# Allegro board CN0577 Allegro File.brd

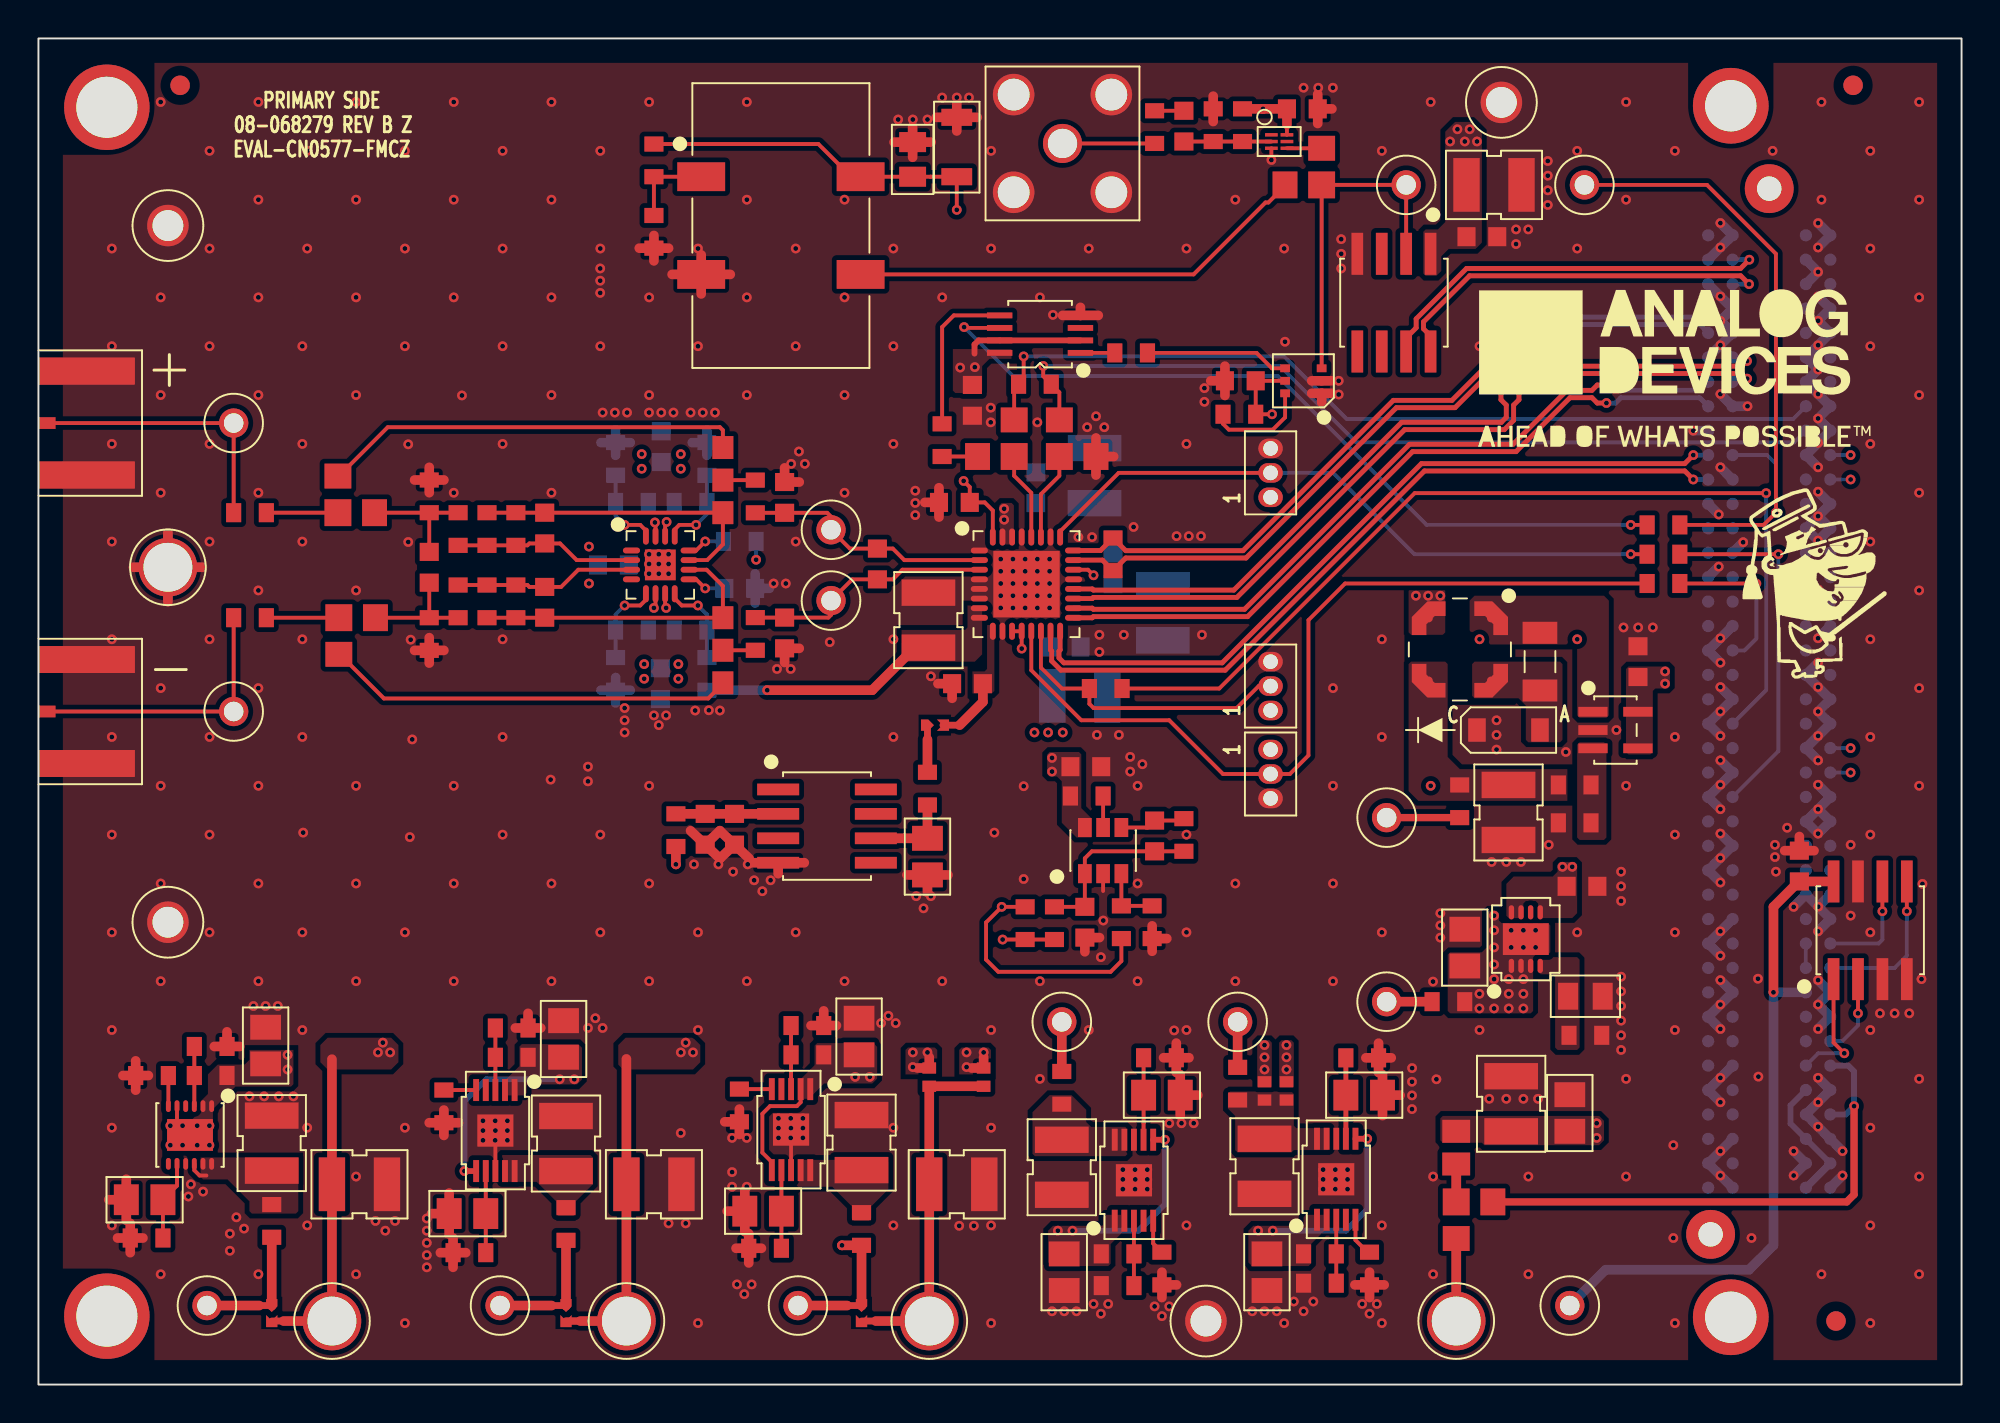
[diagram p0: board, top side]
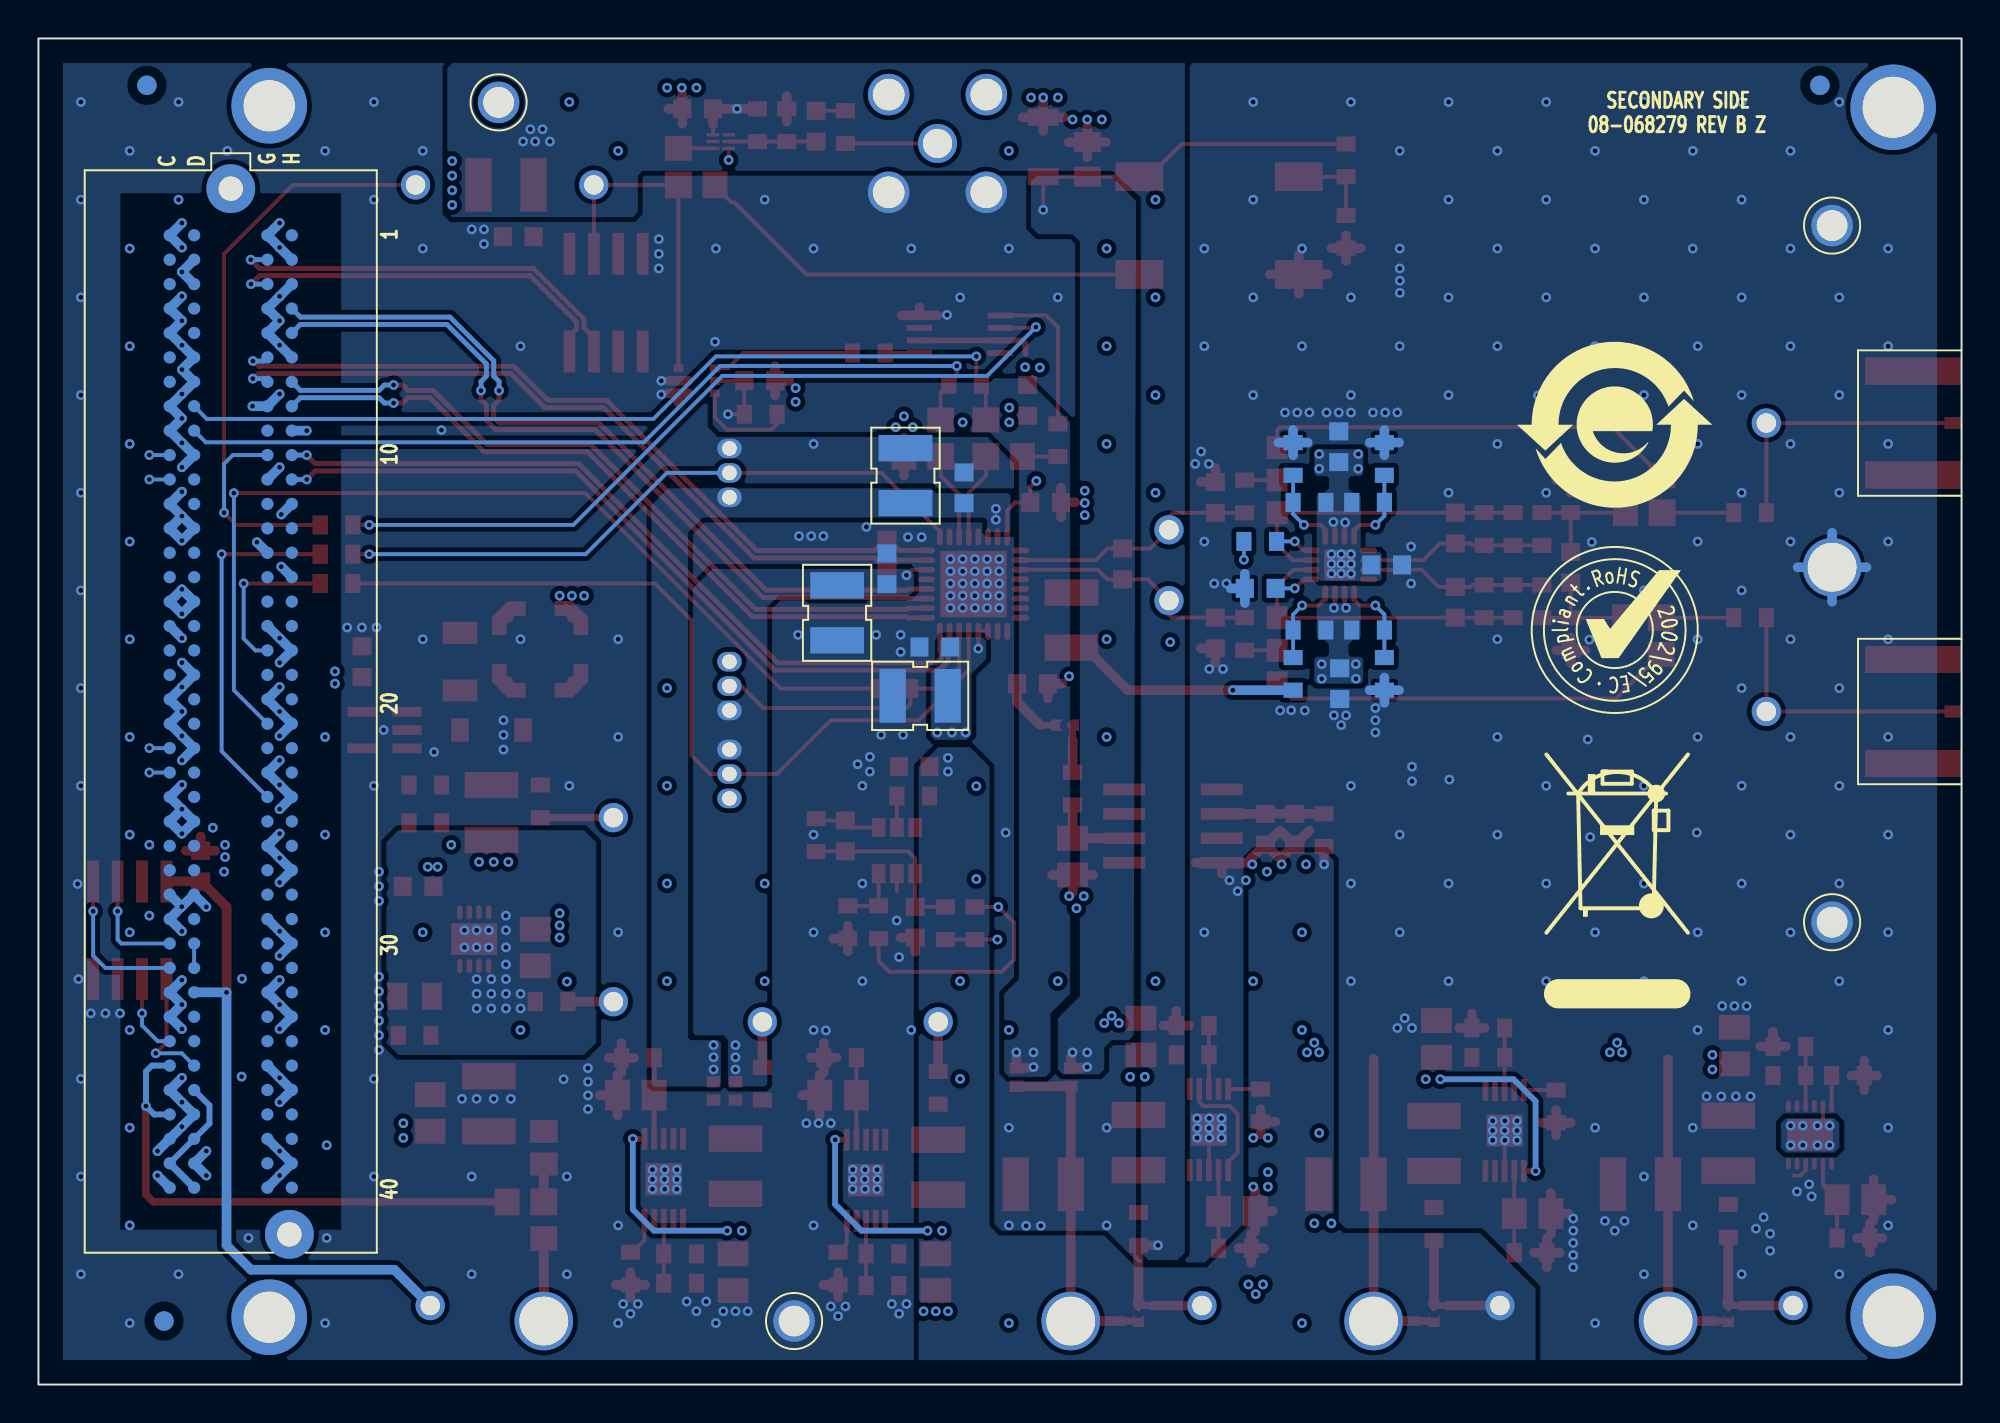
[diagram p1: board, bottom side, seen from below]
Outline 100 x 70 mm; copper layers: TOP, L2_GND, L3_PWR, BOTTOM. Coordinates in mm from the lower left corner of the outline.
Outline path: rectangle 0,0 100,70

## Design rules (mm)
constraint set DEFAULT: 
net group CLK: nets CLK+ CLK-
net group DA: nets DA+ DA-
net group DB: nets DB+ DB-
net group DCO: nets DCO+ DCO-
net group LVDS_CLK: nets LVDS_CLK+ LVDS_CLK-

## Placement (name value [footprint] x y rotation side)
A1  ADA4807-1ARJZ  [SOT23_6-2]  55.36 27.77 0 top
C1  1uF  [C0603]  34.67 28.88 90 top
C2  0.1uF  [C0603]  36.2 28.88 270 top
C3  10UF  [C1210H110]  47.75 10.41 0 top
C4  4.7uF  [C0805H53]  42.67 18.1 90 top
C5  4.7uF  [C0805H53]  46.23 27.45 270 top
C6  0.1uF  [C0603]  54.46 32.13 0 top
C7  TBD0603  [C0603]  58.04 28.53 270 top
C8  TBD0603  [C0603]  54.41 24.04 270 top
C9  10UF  [C1210H110]  16.69 10.41 0 top
C10  1uF  [C0603]  83.17 37.59 270 top
C11  4.7uF  [C0805H53]  79.63 14.12 270 top
C12  1uF  [C0603]  80.26 25.91 180 top
C13  1UF  [C1206]  78.08 37.59 270 top
C14  10UF  [C1210H110]  76.58 14.6 90 top
C15  10PF  [C0805H30]  80.44 20.19 180 top
C16  4.7uF  [C0805H53]  74.17 22.72 270 top
C17  10UF  [C1210H110]  76.44 29.75 270 top
C18  10UF  [C1210H110]  32 10.41 0 top
C19  4.7uF  [C0805H53]  27.3 17.97 90 top
C20  4.7uF  [C0805H53]  53.34 5.84 270 top
C21  4.7uF  [C0805H53]  63.88 5.84 270 top
C22  4.7uF  [C0805H53]  11.81 17.63 90 top
C23  4.7uF  [C0805H53]  22.31 8.89 180 top
C24  4.7uF  [C0805H53]  58.42 15.05 0 top
C25  4.7uF  [C0805H53]  68.94 15.05 0 top
C26  4.7uF  [C0805H53]  5.52 9.61 180 top
C27  10UF  [C1210H110]  27.43 12.53 90 top
C28  10UF  [C1210H110]  53.21 11.3 270 top
C29  10UF  [C1210H110]  63.75 11.35 270 top
C30  10UF  [C1210H110]  12.13 12.56 90 top
C31  0.1uF  [C0603]  75.06 59.69 0 top
C32  10UF  [C1210H110]  75.69 62.38 0 top
C33  0.1uF  [C0603]  29.89 42.62 180 bottom
C34  0.1uF  [C0603]  62.5 52.2 180 top
C41  TBD0603  [C0603]  43.63 42.67 270 top
C42  82pF  [C0603]  38.8 46.13 90 top
C43  82pF  [C0603]  38.8 39.08 270 top
C44  0.1uF  [C0603]  48.31 36.45 180 top
C45  0.1uF  [C0603]  47.63 45.87 180 top
C46  10UF  [C1210H110]  46.28 39.75 90 top
C47  10UF  [C1210H110]  54.91 47.27 90 bottom
C48  10UF  [C1210H110]  54.15 35.81 0 bottom
C49  0.1uF  [C0603]  53.39 38.35 0 bottom
C50  0.1uF  [C0603]  51.87 46.63 90 bottom
C51  0.1uF  [C0603]  55.88 42.42 90 bottom
C52  10UF  [C1210H110]  58.47 40.13 270 bottom
C53  0.1uF  [C0603]  91.57 26.96 90 top
C56  1.8pF  [C0603]  20.32 42.5 270 top
C57  0.1uF  [C0603]  32.38 48.77 90 bottom
C58  1.8pF  [C0603]  26.32 40.68 270 top
C59  0.1uF  [C0603]  32.34 36.45 270 bottom
C60  1.8pF  [C0603]  26.32 44.54 90 top
C61  0.1uF  [C0603]  36.47 41.4 0 bottom
C62  10PF  [C0805H30]  45.46 63.71 270 top
C63  22uF  [C1206H71-2]  47.75 64.35 90 top
C64  0.1uF  [C0603]  59.56 65.44 270 top
C65  0.1uF  [C0603]  65.72 66.34 0 top
C66  0.1uF  [C0603]  48.56 51.18 270 top
C67  4.7uF  [C0805H53]  37.68 9.02 180 top
C68  10UF  [C1210H110]  42.8 12.58 90 top
D1  MBR0520LT1G  [SOD123-2]  76.44 34.04 0 top
E1  600OHM AT 100MEGHZ  [L0805]  73.72 12.32 90 top
E2  30OHM AT 100MEGHZ  [L0402]  64.9 15.27 90 top
E3  30OHM AT 100MEGHZ  [L0402]  63.75 15.27 90 top
E4  30OHM AT 100MEGHZ  [L0402]  46.32 15.98 90 top
E5  30OHM AT 100MEGHZ  [L0402]  49.15 15.98 90 top
EXTPWR  2501-2-00-80-00-00-07-0  [CNMILLMAX2501]  73.72 3.3 0 top
GND  2501-2-00-80-00-00-07-0  [CNMILLMAX2501]  6.73 42.5 0 top
J1  60312202114513  [CNSMARAL559W250H131]  0 50 180 top
J2  60312202114513  [CNSMARAL559W250H131]  0 35 180 top
J3  5-1814832-2  [CNTYCO1814832]  53.25 64.54 0 top
JP2  3PIN_JUMPER_SM  [3PINJUMPER_0603]  74.68 9.5 180 top
JP6  3PINJUMPER0603  [JUMPER0603_3P]  35.59 47.03 90 top
JP7  3PINJUMPER0603  [JUMPER0603_3P]  35.59 38.18 270 top
JP9  3PIN_JUMPER_SM  [3PINJUMPER_0603]  49.78 48.26 0 top
JP10  3PIN_JUMPER_SM  [3PINJUMPER_0603]  53.09 49.21 270 top
JP11  3PIN_JUMPER_SM  [3PINJUMPER_0603]  15.57 46.29 270 top
JP12  3PIN_JUMPER_SM  [3PINJUMPER_0603]  16.57 39.88 180 top
JP14  3PIN_JUMPER_SM  [3PINJUMPER_0603]  65.77 62.38 0 top
L1  10uH  [LSMSQ189H118]  73.91 38.23 180 top
NOREF  -  []  362.42 198.88 0 top
NOREF#2  -  []  0 70 0 top
NOREF#3  -  []  0 0 0 top
NOREF#4  -  [unnamed#2]  88 66.5 0 top
NOREF#5  -  []  100 0 0 top
NOREF#6  -  []  7.62 323.21 0 top
NOREF#7  -  []  271.84 198.88 0 top
NOREF#8  -  [unnamed#2]  93.47 3.3 0 top
NOREF#9  -  []  100 0 90 top
NOREF#10  -  []  147 173.93 0 top
NOREF#11  -  [unnamed#2]  94.36 67.56 0 top
NOREF#12  -  []  74.3 229.24 0 top
NOREF#13  -  []  100 0 90 top
NOREF#14  -  []  362.75 209.04 0 top
NOREF#15  -  []  92.36 41.66 0 top
NOREF#16  -  []  -76.2 -76.2 0 top
NOREF#17  -  [unnamed#2]  88 3.5 0 top
NOREF#18  -  []  100 70 180 top
NOREF#19  -  []  284.29 209.04 90 top
NOREF#20  -  []  65.79 170.81 270 top
NOREF#21  -  []  3.56 3.56 0 top
NOREF#22  -  []  0 70 270 top
NOREF#23  -  []  84.5 52.83 0 top
NOREF#24  -  []  -76.2 -76.2 0 top
NOREF#25  -  []  0 0 0 top
NOREF#26  -  []  -7.24 105.28 0 top
NOREF#27  -  []  271.84 184.91 0 top
NOREF#28  -  [unnamed#2]  7.37 67.56 0 top
NOREF#29  -  []  350.02 90.8 0 top
NOREF#30  -  []  -56.01 289.94 0 top
NOREF#31  -  []  338.9 195.07 0 top
NOREF#32  -  []  -76.2 -76.2 0 top
NOREF#33  -  [unnamed#2]  3.56 66.42 0 top
NOREF#34  -  [unnamed#2]  3.56 3.56 0 top
NOREF#35  -  []  0 70 0 top
NOREF#36  -  []  0 0 0 top
NOREF#37  -  []  3.56 3.56 0 top
NOREF#38  -  []  394.78 203.96 0 top
NOREF#39  -  [unnamed#2]  93.47 3.3 180 bottom
NOREF#40  -  []  18.03 39.24 180 bottom
NOREF#41  -  []  18.03 49.91 180 bottom
NOREF#42  -  []  8.64 36.45 180 bottom
NOREF#43  -  [unnamed#2]  94.36 67.56 180 bottom
NOREF#44  -  [unnamed#2]  7.37 67.56 180 bottom
P1  FTS-103-01-F-S  [CN1X3H159]  64.07 33.02 270 top
P2  FTS-103-01-F-S  [CN1X3H159]  64.07 35.05 90 top
P3  FTS-103-01-F-S  [CN1X3H159]  64.07 46.14 90 top
P4  ASP-134604-01  [CNSAMTECASP-134604-01]  90 35 270 bottom
P5  NCSOLDER_BRIDGE  [NCSB]  46.61 34.29 0 top
P6  NCSOLDER_BRIDGE  [NCSB]  27.43 3.73 270 top
P7  NCSOLDER_BRIDGE  [NCSB]  12.13 3.73 270 top
P8  NCSOLDER_BRIDGE  [NCSB]  42.8 3.73 270 top
R1  0  [R0603]  33.15 28.83 90 top
R2  100K  [R0603]  39.98 17.14 0 top
R3  0  [R0603]  46.23 30.99 90 top
R4  0  [R0603]  56.31 24.04 90 top
R5  0  [R0603]  54.51 30.61 180 top
R6  TBD0603  [R0603]  57.91 24.04 270 top
R7  0  [R0603]  51.31 23.99 270 top
R8  0  [R0603]  59.56 28.58 270 top
R9  0  [R0603]  52.83 23.99 270 top
R10  750K  [R0603]  80.44 18.16 180 top
R11  18.2K  [R0603]  79.88 31.18 180 top
R12  13K  [R0603]  79.88 29.21 0 top
R13  0  [R0603]  73.32 19.91 180 top
R14  0  [R0603]  73.9 30.33 270 top
R15  100K  [R0603]  24.61 17.02 0 top
R16  22.1K  [R0603]  24.61 18.54 180 top
R17  100K  [R0603]  56.12 6.79 180 top
R18  22.1K  [R0603]  56.12 5.14 0 top
R19  100K  [R0603]  66.64 6.79 180 top
R20  22.1K  [R0603]  66.64 5.27 180 top
R21  100K  [R0603]  8.95 16.07 0 top
R22  80.6K  [R0603]  8.95 17.58 180 top
R23  68.1K  [R0603]  22.41 6.86 180 top
R24  51.1K  [R0603]  58.32 16.99 180 top
R25  24.9K  [R0603]  68.83 16.99 180 top
R26  4.99K  [R0603]  5.62 7.62 0 top
R27  1.5K  [R0603]  21.08 14.46 90 top
R28  1.5K  [R0603]  58.42 6.03 90 top
R29  39.2K  [R0603]  5.91 16.07 0 top
R30  1.21K  [R0603]  69.22 6.03 90 top
R31  0  [R0603]  27.43 8.35 270 top
R32  1K  [R0603]  84.5 41.66 0 top
R33  0  [R0603]  53.21 15.43 90 top
R34  1K  [R0603]  84.5 43.18 0 top
R35  0  [R0603]  62.36 15.65 90 top
R36  0  [R0603]  12.13 8.51 270 top
R37  0  [R0603]  62.45 50.46 0 top
R45  1K  [R0603]  32 63.66 90 top
R46  1K  [R0603]  32 59.94 90 top
R53  24.9  [R0603]  37.28 46.18 270 top
R54  24.9  [R0603]  37.28 39.03 90 top
R55  1K  [R0603]  55.5 36.2 0 top
R56  100  [R0603]  51.82 52.02 0 top
R57  100  [R0603]  55.88 43.17 270 top
R58  0  [R0603]  11 39.88 180 top
R59  0  [R0603]  11 45.34 180 top
R60  0  [R0603]  20.32 46.19 270 top
R61  0  [R0603]  20.32 39.03 270 top
R62  1K  [R0603]  21.82 44.49 270 top
R63  1K  [R0603]  21.82 40.73 90 top
R64  0  [R0603]  30.01 36.96 90 bottom
R65  0  [R0603]  30.01 48.13 270 bottom
R66  0  [R0603]  30.86 39.24 180 bottom
R67  0  [R0603]  30.86 45.87 180 bottom
R68  20K  [R0603]  24.82 40.73 270 top
R69  1K  [R0603]  23.32 40.73 270 top
R70  20K  [R0603]  24.82 44.49 90 top
R71  0  [R0603]  33.91 39.24 0 bottom
R72  1K  [R0603]  23.32 44.49 90 top
R73  0  [R0603]  33.91 45.87 0 bottom
R74  0  [R0603]  34.76 36.96 270 bottom
R75  0  [R0603]  34.76 48.13 90 bottom
R76  0  [R0603]  36.47 43.84 180 bottom
R77  49.9  [R0603]  58.04 65.39 90 top
R78  1K  [R0603]  62.61 65.49 90 top
R79  1K  [R0603]  61.09 65.49 270 top
R80  33.2  [R0603]  56.82 53.65 180 top
R82  33.2  [R0603]  84.5 44.7 180 top
R83  33.2  [R0603]  46.99 49.11 270 top
R84  22.1K  [R0603]  39.98 18.67 180 top
R85  33.2K  [R0603]  37.78 7.09 180 top
R86  1.21K  [R0603]  36.45 14.51 90 top
R88  0  [R0603]  42.8 8.09 270 top
TP1  RED  [CNKEY5001TP]  70.1 19.91 0 top
TP2  BLK  [CNKEY5005-9TP]  6.73 24.04 0 top
TP3  RED  [CNKEY5001TP]  70.1 29.48 0 top
TP4  BLK  [CNKEY5005-9TP]  6.73 60.27 0 top
TP5  BLK  [CNKEY5005-9TP]  76.07 66.67 0 top
TP6  BLK  [CNKEY5005-9TP]  60.71 3.3 0 top
TP7  RED  [CNKEY5001TP]  24 4.11 0 top
TP8  RED  [CNKEY5001TP]  53.21 18.86 0 top
TP9  RED  [CNKEY5001TP]  62.36 18.86 0 top
TP10  RED  [CNKEY5001TP]  8.76 4.11 0 top
TP11  RED  [CNKEY5001TP]  41.21 44.45 0 top
TP12  RED  [CNKEY5001TP]  41.21 40.77 0 top
TP13  RED  [CNKEY5001TP]  79.63 4.11 0 top
TP14  RED  [CNKEY5001TP]  10.15 50 0 top
TP15  RED  [CNKEY5001TP]  10.15 35 0 top
TP16  RED  [CNKEY5001TP]  71.12 62.38 0 top
TP17  RED  [CNKEY5001TP]  80.39 62.38 0 top
TP18  RED  [CNKEY5001TP]  39.5 4.11 0 top
U1  LTC2387CUH-18#PBF  [QFN32_5X5_PAD3_45X3_45]  51.38 41.62 270 top
U2  ADR4520ARZ  [SO8]  41 29.04 270 top
U3  LT1931ES5#TRMPBF  [TSOT-5]  82 34.04 270 top
U4  LT3080EDD#PBF  [DFN8_3X3_PAD2_38X1_65]  77.34 23.16 0 top
U5  LT3042EMSE#PBF  [MSOP10_PAD1_88X1_68]  23.76 13.21 180 top
U6  LT3042EMSE#PBF  [MSOP10_PAD1_88X1_68]  56.96 10.62 0 top
U7  LT3042EMSE#PBF  [MSOP10_PAD1_88X1_68]  67.48 10.67 0 top
U8  LT3094EDD#PBF  [DFN12_3X3_PAD2_38X1_65]  7.88 12.98 180 top
U9  M24C02-RMN6TP  [SO8]  95.25 23.62 0 top
U10  ADA4945-1ACPZ-R7  [QFN16_3X3_PAD1_6X1_6]  32.34 42.62 270 top
U11  ADG3241BKSZ  [SC70-6]  65.78 52.2 90 top
U12  74LVC1G04FW4-7  [DFN6_1X1]  64.52 64.64 270 top
U13  SN74LVC1G74DCTR  [MSOP8-2]  52.08 54.62 90 top
U14  LT3042EMSE#PBF  [MSOP10_PAD1_88X1_68]  39.13 13.26 180 top
U15  ADN4661BRZ  [SO8]  70.48 56.26 180 top
UNK3.3V  2501-2-00-80-00-00-07-0  [CNMILLMAX2501]  46.32 3.3 0 top
UNK+6.8V  2501-2-00-80-00-00-07-0  [CNMILLMAX2501]  30.57 3.3 90 top
UNK-1V  2501-2-00-80-00-00-07-0  [CNMILLMAX2501]  15.26 3.3 0 top
Y1  120MEGHZ  [YSML563W343H217_A]  38.61 60.27 270 top

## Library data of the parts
A1 = ADA4807_1: User Part Number: UPN; Tolerance: N/A; alternate symbols: (); part number: ADA4807_1_SM-ADA4807-1ARJZ,E024029,SOT23_6-2; tolerance: N/A
C1 C10 C12 = CAP: User Part Number: UPN; Tolerance: 10; alternate symbols: (C0603L); part number: CAP_SM-1UF,25V,10,E026591,C0603; tolerance: 10
C2 C6 C31 C33 C34 C44 C45 C49-C51 C53 C57 C59 C61 C64-C66 = CAP: User Part Number: UPN; Tolerance: 10; alternate symbols: (C0603L); part number: CAP_SM-0.1UF,16V,10,E026560,C0603; tolerance: 10
C3 C9 C14 C17 C18 C27-C30 C32 C46-C48 C52 C68 = CAP: Tolerance: 10; User Part Number: UPN; alternate symbols: (); part number: CAP_SM-10UF,50V,10,E048108,C1210H110; tolerance: 10
C4 C5 C11 C16 C19-C26 C67 = CAP: Tolerance: 10; User Part Number: UPN; alternate symbols: (); part number: CAP_SM-4.7UF,25V,10,E025752,C0805H53; tolerance: 10
C7 C8 C41 = CAP: User Part Number: UPN; alternate symbols: (C0603L,C0603L_ALT); part number: CAP_SM-TBD0603,TBD0603,TBD0603,E000382,C0603
C13 = CAP: User Part Number: UPN; Tolerance: 10; alternate symbols: (C1206L); part number: CAP_SM-1UF,25V,10,E057338,C1206; tolerance: 10
C15 C62 = CAP: Tolerance: 5; User Part Number: UPN; alternate symbols: (); part number: CAP_SM-10PF,50V,5,E057339,C0805H30; tolerance: 5
C42 C43 = CAP: User Part Number: UPN; Tolerance: 5; alternate symbols: (C0603L); part number: CAP_SM-82PF,50V,5,E000414,C0603; tolerance: 5
C56 C58 C60 = CAP: User Part Number: UPN; Tolerance: 5; alternate symbols: (C0603L); part number: CAP_SM-1.8PF,50V,5,E000402,C0603; tolerance: 5
C63 = CAP: Tolerance: 10; User Part Number: UPN; alternate symbols: (C1206_ALT); part number: CAP_SM-22UF,10V,10,E025454,C1206H71-2; tolerance: 10
D1 = DIOSCHOTTKY: User Part Number: UPN; Tolerance: N/A; alternate symbols: (); part number: DIOSCHOTTKY_SM-MBR0520LT1G,20V,N/A,E019662,SOD123-2; tolerance: N/A
E1 = FERRITE: User Part Number: UPN; Tolerance: 25; alternate symbols: (L0805L); part number: FERRITE_SM-600OHM AT 100MEGHZ,25,E026974,L0805; tolerance: 25
E2-E5 = FERRITE: User Part Number: UPN; Tolerance: 25; alternate symbols: (L0402L); part number: FERRITE_SM-30OHM AT 100MEGHZ,25,E021489,L0402; tolerance: 25
EXTPWR GND UNK3.3V UNK+6.8V UNK-1V = CNTP1P: User Part Number: UPN; Tolerance: N/A; alternate symbols: (); part number: CNTP1P_TH-2501-2-00-80-00-00-07-0,E031108,CNMILLMAX2501; tolerance: N/A
J1 J2 = CNBNC5P: User Part Number: UPN; Tolerance: N/A; alternate symbols: (); part number: CNBNC5P_SM-60312202114513,E049020,CNSMARAL559W250H131; tolerance: N/A
J3 = CNBNC5P: Tolerance: N/A; User Part Number: UPN; alternate symbols: (); part number: CNBNC5P_TH-5-1814832-2,E010606,CNTYCO1814832; tolerance: N/A
JP2 JP9-JP12 JP14 = NC3P_JMPR: Tolerance: N/A; User Part Number: UPN; alternate symbols: (); part number: NC3P_JMPR_SM-3PIN_JUMPER_SM,E008052,3PINJUMPER_0603; tolerance: N/A
JP6 JP7 = NC3P_JMPR: Tolerance: N/A; User Part Number: UPN; alternate symbols: (); part number: NC3P_JMPR_SM-3PINJUMPER_0603,E031098,JUMPER0603_3P; tolerance: N/A
L1 = IND_4P_V2: User Part Number: UPN; Tolerance: 20; alternate symbols: (); part number: IND_4P_V2_SM-10UH,20,E020038,LSMSQ189H118; tolerance: 20
P1-P3 = CN3P: Tolerance: N/A; User Part Number: UPN; alternate symbols: (); part number: CN3P_TH-FTS-103-01-F-S,E021702,CN1X3H159; tolerance: N/A
P4 = CN160P_CDGH_V2: User Part Number: UPN; Tolerance: N/A; alternate symbols: (CNSAMTECASP-134604-01_KITTRF,CNSAMTECASP-134604-01_EVKP); part number: CN160P_CDGH_V2_SM-ASP-134604-01,E011383,CNSAMTECASP-134604-01; tolerance: N/A
P5-P8 = NC2P: User Part Number: UPN; Tolerance: N/A; alternate symbols: (); part number: NC2P_SM-NCSOLDER_BRIDGE,E043778,NCSB; tolerance: N/A
R1 R3-R5 R7-R9 R13 R14 R31 R33 R35-R37 R58-R61 R64-R67 R71 R73-R76 R88 = RES: User Part Number: UPN; Tolerance: JUMPER; alternate symbols: (R0603L); part number: RES_SM-0,E027148,1/4W,JUMPER,R0603; tolerance: JUMPER
R2 R15 R17 R19 R21 = RES: User Part Number: UPN; Tolerance: 1; alternate symbols: (R0603L); part number: RES_SM-100K,E017050,1/10W,1,R0603; tolerance: 1
R6 = RES: User Part Number: UPN; alternate symbols: (R0603L); part number: RES_SM-TBD0603,E004050,TBD0603,TBD0603,R0603
R10 = RES: User Part Number: UPN; Tolerance: 1; alternate symbols: (R0603L); part number: RES_SM-750K,E031505,1/10W,1,R0603; tolerance: 1
R11 = RES: User Part Number: UPN; Tolerance: 1; alternate symbols: (R0603L); part number: RES_SM-18.2K,E011126,1/10W,1,R0603; tolerance: 1
R12 = RES: User Part Number: UPN; Tolerance: 1; alternate symbols: (R0603L); part number: RES_SM-13K,E020173,1/10W,1,R0603; tolerance: 1
R16 R18 R20 R84 = RES: User Part Number: UPN; Tolerance: 1; alternate symbols: (R0603L); part number: RES_SM-22.1K,E003681,1/10W,1,R0603; tolerance: 1
R22 = RES: User Part Number: UPN; Tolerance: 1; alternate symbols: (R0603L); part number: RES_SM-80.6K,E023402,1/10W,1,R0603; tolerance: 1
R23 = RES: User Part Number: UPN; Tolerance: 1; alternate symbols: (R0603L); part number: RES_SM-68.1K,E042827,1/10W,1,R0603; tolerance: 1
R24 = RES: User Part Number: UPN; Tolerance: 1; alternate symbols: (R0603L); part number: RES_SM-51.1K,E026198,1/10W,1,R0603; tolerance: 1
R25 = RES: User Part Number: UPN; Tolerance: 1; alternate symbols: (R0603L); part number: RES_SM-24.9K,E025629,1/10W,1,R0603; tolerance: 1
R26 = RES: User Part Number: UPN; Tolerance: 1; alternate symbols: (R0603L); part number: RES_SM-4.99K,E003726,1/10W,1,R0603; tolerance: 1
R27 R28 = RES: User Part Number: UPN; Tolerance: 1; alternate symbols: (R0603L); part number: RES_SM-1.5K,E010156,1/10W,1,R0603; tolerance: 1
R29 = RES: User Part Number: UPN; Tolerance: 1; alternate symbols: (R0603L); part number: RES_SM-39.2K,E025112,1/10W,1,R0603; tolerance: 1
R30 R86 = RES: User Part Number: UPN; Tolerance: 1; alternate symbols: (R0603L); part number: RES_SM-1.21K,E011249,1/10W,1,R0603; tolerance: 1
R32 R34 R45 R46 R55 R62 R63 R69 R72 R78 R79 = RES: User Part Number: UPN; Tolerance: 1; alternate symbols: (R0603L); part number: RES_SM-1K,E029591,1/10W,1,R0603; tolerance: 1
R53 R54 = RES: User Part Number: UPN; Tolerance: 1; alternate symbols: (R0603L); part number: RES_SM-24.9,E003696,1/10W,1,R0603; tolerance: 1
R56 R57 = RES: User Part Number: UPN; Tolerance: 1; alternate symbols: (R0603L); part number: RES_SM-100,E003668,1/10W,1,R0603; tolerance: 1
R68 R70 = RES: User Part Number: UPN; Tolerance: 1; alternate symbols: (R0603L); part number: RES_SM-20K,E017927,1/10W,1,R0603; tolerance: 1
R77 = RES: User Part Number: UPN; Tolerance: 1; alternate symbols: (R0603L); part number: RES_SM-49.9,E003673,1/10W,1,R0603; tolerance: 1
R80 R82 R83 = RES: User Part Number: UPN; Tolerance: 1; alternate symbols: (R0603L); part number: RES_SM-33.2,E010479,1/10W,1,R0603; tolerance: 1
R85 = RES: User Part Number: UPN; Tolerance: 1; alternate symbols: (R0603L); part number: RES_SM-33.2K,E028266,1/10W,1,R0603; tolerance: 1
TP1 TP3 TP7-TP18 = CNTP1P: Tolerance: N/A; User Part Number: UPN; alternate symbols: (); part number: CNTP1P_TH-RED,E016323,CNKEY5001TP; tolerance: N/A
TP2 TP4-TP6 = CNTP1P: Tolerance: N/A; User Part Number: UPN; alternate symbols: (); part number: CNTP1P_TH-BLK,E015367,CNKEY5005-9TP; tolerance: N/A
U1 = ADLTC2387_18: User Part Number: UPN; Tolerance: N/A; alternate symbols: (); part number: ADLTC2387_18_SM-LTC2387CUH-18#PBF,E058101,QFN32_5X5_PAD3_45X3_45; tolerance: N/A
U2 = ADR45XX: Tolerance: N/A; User Part Number: UPN; alternate symbols: (); part number: ADR45XX_SM-ADR4520ARZ,E017487,SO8; tolerance: N/A
U3 = LINLT1931: User Part Number: UPN; Tolerance: N/A; alternate symbols: (); part number: LINLT1931_SM-LT1931ES5#TRMPBF,E030339,TSOT-5; tolerance: N/A
U4 = ADLT3080: User Part Number: UPN; Tolerance: N/A; alternate symbols: (); part number: ADLT3080_SM-LT3080EDD#PBF,E038067,DFN8_3X3_PAD2_38X1_65; tolerance: N/A
U5-U7 U14 = LINLT3042: User Part Number: UPN; Tolerance: N/A; alternate symbols: (); part number: LINLT3042_SM-LT3042EMSE#PBF,E029803,MSOP10_PAD1_88X1_68; tolerance: N/A
U8 = LINLT3094: User Part Number: UPN; Tolerance: N/A; alternate symbols: (); part number: LINLT3094_SM-LT3094EDD#PBF,E033630,DFN12_3X3_PAD2_38X1_65; tolerance: N/A
U9 = ICM24CXX: Tolerance: N/A; User Part Number: UPN; alternate symbols: (); part number: ICM24CXX_SM-M24C02-RMN6TP,E018349,SO8; tolerance: N/A
U10 = ADA4945_1: User Part Number: UPN; Tolerance: N/A; alternate symbols: (); part number: ADA4945_1_SM-ADA4945-1ACPZ-R7,E028779,QFN16_3X3_PAD1_6X1_6; tolerance: N/A
U11 = ADG3241: Tolerance: N/A; User Part Number: UPN; alternate symbols: (); part number: ADG3241_SM-ADG3241BKSZ,E021262,SC70-6; tolerance: N/A
U12 = 741G04_V2: Tolerance: N/A; User Part Number: UPN; alternate symbols: (); part number: 741G04_V2_SM-74LVC1G04FW4-7,E058692,DFN6_1X1; tolerance: N/A
U13 = 741G74_V3: Tolerance: N/A; User Part Number: UPN; alternate symbols: (); part number: 741G74_V3_SM-SN74LVC1G74DCTR,E057341,MSOP8-2; tolerance: N/A
U15 = ADN4661: Tolerance: N/A; User Part Number: UPN; alternate symbols: (); part number: ADN4661_SM-ADN4661BRZ,E013548,SO8; tolerance: N/A
Y1 = XTALOSC4P_V29: User Part Number: UPN; Tolerance: N/A; alternate symbols: (); part number: XTALOSC4P_V29_SM-120MEGHZ,E054211,YSML563W343H217_A; tolerance: N/A

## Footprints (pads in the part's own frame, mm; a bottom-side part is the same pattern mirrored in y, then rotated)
3PINJUMPER_0603
  rect 1.295x1.397 smd: 1(-0.953,0)
  rect 1.397x1.397 smd: 2(0.953,0)
  rect 1.397x1.295 smd: 3(0.953,1.905)
C0603
  rect 0.94x0.991 smd: 1(-0.8,0) 2(0.8,0)
C0805H30
  rect 1.041x1.397 smd: 1(-0.9,0) 2(0.9,0)
C0805H53
  rect 1.295x1.6 smd: 1(-0.953,0) 2(0.953,0)
C1206
  rect 1.143x1.803 smd: 1(-1.5,0) 2(1.5,0)
C1206H71-2
  rect 0.889x1.6 smd: 1(-1.544,0) 2(1.544,0)
C1210H110
  rect 1.372x2.794 smd: 1(-1.431,0) 2(1.431,0)
CN1X3H159
  oval 1.016x1.27 hole 0.762: 1(0,0) 2(1.27,0) 3(2.54,0)
CNKEY5001TP
  round 1.524 hole 1.016: 1(0,0)
CNKEY5005-9TP
  round 2.159 hole 1.6: 1(0,0)
CNMILLMAX2501
  round 3.048 hole 2.54: 1(0,0)
CNSAMTECASP-134604-01
  round 2.54 hole 1.27 unplated: (-27.191,0) (27.191,3.048)
  round 0.635 smd: C1(-24.765,-3.175) C2(-23.495,-3.175) C3(-22.225,-3.175) C4(-20.955,-3.175) C5(-19.685,-3.175) C6(-18.415,-3.175) C7(-17.145,-3.175) C8(-15.875,-3.175) C9(-14.605,-3.175) C10(-13.335,-3.175) C11(-12.065,-3.175) C12(-10.795,-3.175) C13(-9.525,-3.175) C14(-8.255,-3.175) C15(-6.985,-3.175) C16(-5.715,-3.175) C17(-4.445,-3.175) C18(-3.175,-3.175) C19(-1.905,-3.175) C20(-0.635,-3.175) C21(0.635,-3.175) C22(1.905,-3.175) C23(3.175,-3.175) C24(4.445,-3.175) C25(5.715,-3.175) C26(6.985,-3.175) C27(8.255,-3.175) C28(9.525,-3.175) C29(10.795,-3.175) C30(12.065,-3.175) C31(13.335,-3.175) C32(14.605,-3.175) C33(15.875,-3.175) C34(17.145,-3.175) C35(18.415,-3.175) C36(19.685,-3.175) C37(20.955,-3.175) C38(22.225,-3.175) C39(23.495,-3.175) C40(24.765,-3.175) D1(-24.765,-1.905) D2(-23.495,-1.905) D3(-22.225,-1.905) D4(-20.955,-1.905) D5(-19.685,-1.905) D6(-18.415,-1.905) D7(-17.145,-1.905) D8(-15.875,-1.905) D9(-14.605,-1.905) D10(-13.335,-1.905) D11(-12.065,-1.905) D12(-10.795,-1.905) D13(-9.525,-1.905) D14(-8.255,-1.905) D15(-6.985,-1.905) D16(-5.715,-1.905) D17(-4.445,-1.905) D18(-3.175,-1.905) D19(-1.905,-1.905) D20(-0.635,-1.905) D21(0.635,-1.905) D22(1.905,-1.905) D23(3.175,-1.905) D24(4.445,-1.905) D25(5.715,-1.905) D26(6.985,-1.905) D27(8.255,-1.905) D28(9.525,-1.905) D29(10.795,-1.905) D30(12.065,-1.905) D31(13.335,-1.905) D32(14.605,-1.905) D33(15.875,-1.905) D34(17.145,-1.905) D35(18.415,-1.905) D36(19.685,-1.905) D37(20.955,-1.905) D38(22.225,-1.905) D39(23.495,-1.905) D40(24.765,-1.905) G1(-24.765,1.905) G2(-23.495,1.905) G3(-22.225,1.905) G4(-20.955,1.905) G5(-19.685,1.905) G6(-18.415,1.905) G7(-17.145,1.905) G8(-15.875,1.905) G9(-14.605,1.905) G10(-13.335,1.905) G11(-12.065,1.905) G12(-10.795,1.905) G13(-9.525,1.905) G14(-8.255,1.905) G15(-6.985,1.905) G16(-5.715,1.905) G17(-4.445,1.905) G18(-3.175,1.905) G19(-1.905,1.905) G20(-0.635,1.905) G21(0.635,1.905) G22(1.905,1.905) G23(3.175,1.905) G24(4.445,1.905) G25(5.715,1.905) G26(6.985,1.905) G27(8.255,1.905) G28(9.525,1.905) G29(10.795,1.905) G30(12.065,1.905) G31(13.335,1.905) G32(14.605,1.905) G33(15.875,1.905) G34(17.145,1.905) G35(18.415,1.905) G36(19.685,1.905) G37(20.955,1.905) G38(22.225,1.905) G39(23.495,1.905) G40(24.765,1.905) H1(-24.765,3.175) H2(-23.495,3.175) H3(-22.225,3.175) H4(-20.955,3.175) H5(-19.685,3.175) H6(-18.415,3.175) H7(-17.145,3.175) H8(-15.875,3.175) H9(-14.605,3.175) H10(-13.335,3.175) H11(-12.065,3.175) H12(-10.795,3.175) H13(-9.525,3.175) H14(-8.255,3.175) H15(-6.985,3.175) H16(-5.715,3.175) H17(-4.445,3.175) H18(-3.175,3.175) H19(-1.905,3.175) H20(-0.635,3.175) H21(0.635,3.175) H22(1.905,3.175) H23(3.175,3.175) H24(4.445,3.175) H25(5.715,3.175) H26(6.985,3.175) H27(8.255,3.175) H28(9.525,3.175) H29(10.795,3.175) H30(12.065,3.175) H31(13.335,3.175) H32(14.605,3.175) H33(15.875,3.175) H34(17.145,3.175) H35(18.415,3.175) H36(19.685,3.175) H37(20.955,3.175) H38(22.225,3.175) H39(23.495,3.175) H40(24.765,3.175)
CNSMARAL559W250H131
  rect 0.889x0.61 smd: 1(-0.445,0)
  rect 5.004x1.397 smd: 2(-2.502,2.701) 3(-2.502,-2.701) 4(-2.502,2.701) 5(-2.502,-2.701)
CNTYCO1814832
  round 2.032 hole 1.524: 1(0,0)
  round 2.159 hole 1.651: 2(-2.54,2.54) 3(2.54,2.54) 4(2.54,-2.54) 5(-2.54,-2.54)
DFN6_1X1
  rect 0.178x0.66 smd: 1(-0.35,-0.405) 2(0,-0.405) 3(0.35,-0.405) 4(0.35,0.405) 5(0,0.405) 6(-0.35,0.405)
DFN8_3X3_PAD2_38X1_65
  oval 0.279x0.737 smd: 1(-0.75,-1.393) 2(-0.25,-1.393) 3(0.25,-1.393) 4(0.75,-1.393) 5(0.75,1.393) 6(0.25,1.393) 7(-0.25,1.393) 8(-0.75,1.393)
  rect 2.388x1.651 smd: PAD(0,0)
DFN12_3X3_PAD2_38X1_65
  oval 0.254x0.61 smd: 1(-1.125,-1.5) 2(-0.675,-1.5) 3(-0.225,-1.5) 4(0.225,-1.5) 5(0.675,-1.5) 6(1.125,-1.5) 7(1.125,1.5) 8(0.675,1.5) 9(0.225,1.5) 10(-0.225,1.5) 11(-0.675,1.5) 12(-1.125,1.5)
  rect 2.388x1.651 smd: PAD(0,0)
JUMPER0603_3P
  rect 1.194x1.092 smd: 1(-1.694,0) 2(0,0) 3(1.694,0)
L0402
  rect 0.584x0.711 smd: 1(-0.475,0) 2(0.475,0)
L0805
  rect 1.194x1.448 smd: 1(-0.85,0) 2(0.85,0)
LSMSQ189H118
  custom 0.438x0.438 smd: 1(-1.626,-1.626) 2(1.626,-1.626) 3(1.626,1.626) 4(-1.626,1.626)
MSOP8-2
  rect 0.305x1.321 smd: 1(-0.975,-2.1) 2(-0.325,-2.1) 3(0.325,-2.1) 4(0.975,-2.1) 5(0.975,2.1) 6(0.325,2.1) 7(-0.325,2.1) 8(-0.975,2.1)
MSOP10_PAD1_88X1_68
  rect 0.305x1.143 smd: 1(-1,-2.106) 2(-0.5,-2.106) 3(0,-2.106) 4(0.5,-2.106) 5(1,-2.106) 6(1,2.106) 7(0.5,2.106) 8(0,2.106) 9(-0.5,2.106) 10(-1,2.106)
  rect 1.88x1.676 smd: PAD(0,0)
NCSB
  custom 0.148x0.148 smd: 1(-0.383,0) 2(0.423,0)
QFN16_3X3_PAD1_6X1_6
  oval 0.305x0.889 smd: 1(-0.75,-1.5) 2(-0.25,-1.5) 3(0.25,-1.5) 4(0.75,-1.5) 9(0.75,1.5) 10(0.25,1.5) 11(-0.25,1.5) 12(-0.75,1.5)
  oval 0.889x0.305 smd: 5(1.5,-0.75) 6(1.5,-0.25) 7(1.5,0.25) 8(1.5,0.75) 13(-1.5,0.75) 14(-1.5,0.25) 15(-1.5,-0.25) 16(-1.5,-0.75)
  rect 1.6x1.6 smd: PAD(0,0)
QFN32_5X5_PAD3_45X3_45
  oval 0.305x0.889 smd: 1(-1.75,-2.45) 2(-1.25,-2.45) 3(-0.75,-2.45) 4(-0.25,-2.45) 5(0.25,-2.45) 6(0.75,-2.45) 7(1.25,-2.45) 8(1.75,-2.45) 17(1.75,2.45) 18(1.25,2.45) 19(0.75,2.45) 20(0.25,2.45) 21(-0.25,2.45) 22(-0.75,2.45) 23(-1.25,2.45) 24(-1.75,2.45)
  oval 0.889x0.305 smd: 9(2.45,-1.75) 10(2.45,-1.25) 11(2.45,-0.75) 12(2.45,-0.25) 13(2.45,0.25) 14(2.45,0.75) 15(2.45,1.25) 16(2.45,1.75) 25(-2.45,1.75) 26(-2.45,1.25) 27(-2.45,0.75) 28(-2.45,0.25) 29(-2.45,-0.25) 30(-2.45,-0.75) 31(-2.45,-1.25) 32(-2.45,-1.75)
  rect 3.454x3.454 smd: PAD(0,0)
R0603
  rect 0.787x0.991 smd: 1(-0.85,0) 2(0.85,0)
SC70-6
  rect 0.406x0.508 smd: 1(-0.65,-0.95) 2(0,-0.95) 3(0.65,-0.95) 4(0.65,0.95) 5(0,0.95) 6(-0.65,0.95)
SO8
  rect 0.61x2.184 smd: 1(-1.905,-2.54) 2(-0.635,-2.54) 3(0.635,-2.54) 4(1.905,-2.54) 5(1.905,2.54) 6(0.635,2.54) 7(-0.635,2.54) 8(-1.905,2.54)
SOD123-2
  rect 0.914x1.219 smd: A(1.638,0) C(-1.638,0)
SOT23_6-2
  rect 0.711x0.991 smd: 1(-0.95,-1.2) 2(0,-1.2) 3(0.95,-1.2) 4(0.95,1.2) 5(0,1.2) 6(-0.95,1.2)
TSOT-5
  rect 0.508x1.524 smd: 1(-0.95,-1.17) 2(0,-1.17) 3(0.95,-1.17) 4(0.95,1.17) 5(-0.95,1.17)
unnamed#2
  round 3.937 hole 2.667 unplated: (0,0)
YSML563W343H217_A
  rect 1.499x2.489 smd: 1(-2.54,-4.144) 2(2.54,-4.144) 3(2.54,4.144) 4(-2.54,4.144)

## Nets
+2.5V: C66.1 R35.2(N2) TP9.1(N1) U13.2 U13.7 U13.8(VCC)
+3.3V: C31.1 C32.1 C65.1 P8.1 R78.2(N2) R88.2(N2) TP18.1(N1) U12.6 U15.1(VCC)
+3.3V_CRYSTAL: C62.2(N2) C63.1 E4.2(N2) R45.2(N2) Y1.4(VDD)
+3.3V_TRANSLATOR: C34.1 E5.2(N2) R37.2(N2) U11.5(VCC)
+6.8V: A1.6 C6.1 P6.1 R1.1 R5.2(N2) R31.2(N2) TP7.1(N1)
+7.5V: C4.1 C19.1 C20.1 C21.1 R2.2(N2) R13.2(N2) R15.2(N2) R17.2(N2) R19.2(N2) TP1.1(N1) U5.1 U5.2 U5.6 U6.1 U6.2 U6.6 U7.1 U7.2 U7.6 U14.1 U14.2 U14.6
+12V: C10.2(N2) C11.2(N2) C12.2(N2) C14.1 E1.2(N2) L1.2 U3.4 U3.5(VIN) U4.5(VCONTROL) U4.7 U4.8
+12V_FMC: JP2.1 P4.C35 P4.C37
-1V: P7.1 R36.2(N2) TP10.1(N1)
-3V: C22.1 R14.2(N2) R21.2(N2) TP3.1(N1) U8.1 U8.2 U8.5 U8.PAD
AGND: A1.2 C1.1 C2.2(N2) C3.2(N2) C4.2(N2) C5.2(N2) C6.2(N2) C8.2(N2) C9.2(N2) C10.1 C11.1 C12.1 C14.2(N2) C15.1 C16.1 C17.2(N2) C18.2(N2) C19.2(N2) C20.2(N2) C21.2(N2) C22.2(N2) C23.2(N2) C24.2(N2) C25.2(N2) C26.2(N2) C27.2(N2) C28.2(N2) C29.2(N2) C30.2(N2) C31.2(N2) C32.2(N2) C33.2(N2) C34.2(N2) C42.2(N2) C43.2(N2) C44.2(N2) C45.2(N2) C46.2(N2) C47.2(N2) C48.2(N2) C49.2(N2) C50.2(N2) C51.2(N2) C52.2(N2) C53.2(N2) C57.2(N2) C59.2(N2) C61.2(N2) C62.1 C63.2(N2) C65.2(N2) C66.2(N2) C67.2(N2) C68.2(N2) D1.C GND.1(N1) J1.2 J1.3 J1.4 J1.5(SH4) J2.2 J2.3 J2.4 J2.5(SH4) J3.2 J3.3 J3.4 J3.5(SH4) JP10.3 P1.3(N3) P2.3(N3) P3.3(N3) P4.C1 P4.C4 P4.C5 P4.C8 P4.C9 P4.C12 P4.C13 P4.C16 P4.C17 P4.C20 P4.C21 P4.C24 P4.C25 P4.C28 P4.C29 P4.C32 P4.C33 P4.C36 P4.C38 P4.C40 P4.D2 P4.D3 P4.D6 P4.D7 P4.D10 P4.D13 P4.D16 P4.D19 P4.D22 P4.D25 P4.D28 P4.D37 P4.D39 P4.G1 P4.G4 P4.G5 P4.G8 P4.G11 P4.G14 P4.G17 P4.G20 P4.G23 P4.G26 P4.G29 P4.G32 P4.G35 P4.G38 P4.G40 P4.H2 P4.H3 P4.H6 P4.H9 P4.H12 P4.H15 P4.H18 P4.H21 P4.H24 P4.H27 P4.H30 P4.H33 P4.H36 P4.H39 R6.2(N2) R10.1 R12.1 R16.1 R18.1 R20.2(N2) R22.1 R23.2(N2) R24.1 R25.1 R26.1 R27.1 R28.1 R29.1 R30.1 R46.1 R60.1 R61.2(N2) R64.1 R65.1 R75.2(N2) R79.1 R84.1 R85.2(N2) R86.1 TP2.1(N1) TP4.1(N1) TP5.1(N1) TP6.1(N1) U1.1 U1.4 U1.5 U1.6 U1.10 U1.21 U1.26 U1.29 U1.PAD U2.4 U3.2 U5.8 U5.PAD U6.8 U6.PAD U7.8 U7.PAD U8.9 U9.3 U9.4 U9.7(WC_N) U11.1 U11.2 U12.3 U13.4 U14.8 U14.PAD U15.4 Y1.2
VDD: C48.1 C49.1 R33.2(N2) TP8.1(N1) U1.11 U1.12(VDD_2)
VDDL: C47.1 C50.1 E2.2(N2) P3.1 U1.30 U1.31
3P3VAUX: C53.1 P4.D32 TP13.1(N1) U9.8
+3P3V_FMC: P4.C39 P4.D36 P4.D38 P4.D40
AMP_PWR+: C18.1 C59.1 P6.2(N2) R66.1 R71.1 R76.1 U10.6 U10.7 UNK+6.8V.1
AMP_PWR-: C9.1 C33.1 C57.1 P7.2(N2) R67.1 R73.1 U10.14 U10.15 U10.PAD UNK-1V.1
BYPASS+: JP6.3 JP11.1
BYPASS-: JP7.3 JP12.3
C10: P4.C10
C11: P4.C11
C22: P4.C22
C23: P4.C23
CLK+: P4.G6 R57.1 U1.24
CLK-: P4.G7 R57.2(N2) U1.23
CNV+_EXT: JP9.1 R83.2(N2)
CNV_EN: P4.G10 R82.1 TP17.1(N1)
DA+: P4.H7 U1.18
DA-: P4.H8 U1.17
DB+: P4.H10 U1.16
DB-: P4.H11 U1.15
DCO+: P4.H4 U1.20
DCO-: P4.H5 U1.19
DIFF_OUT+: C60.2(N2) JP6.1 R70.2(N2) R72.2(N2) U10.11
DIFF_OUT-: C58.2(N2) JP7.1 R68.2(N2) R69.2(N2) U10.10
FPGA_CNV+: JP9.3 P4.D8 R56.1
FPGA_CNV-: JP10.1 P4.D9 R56.2(N2)
FPGA_PD_CONTROL: P4.G18 R32.2(N2)
FPGA_TESTPAT_CONTROL: P4.G21 R55.2(N2)
FPGA_TWOLANES_CONTROL: P4.G24 R34.2(N2)
GA0: P4.C34 U9.2
GA1: P4.D35 U9.1
LVDS_CLK+: P4.G2 U15.7
LVDS_CLK-: P4.G3 U15.8
OVDD: C51.1 C52.1 E3.2(N2) P1.1 P2.1 U1.22
REFBUF: C46.1 R74.2(N2) U1.7 U1.8
REFIN_OVERDRIVE: C44.1 P5.2(N2) U1.9
SCL: P4.C30 U9.6
SDA: P4.C31 U9.5
UNNAMED_3_ADA48071_I32_: A1.4 C7.1 R8.1
UNNAMED_3_ADA48071_I32__2: A1.3 R4.2(N2) R6.1
UNNAMED_3_ADA48071_I32_DISABLEN: A1.5 R5.1
UNNAMED_3_ADA48071_I32_VOUT: A1.1(VOUT) C7.2(N2) C8.1 R8.2(N2) R9.1
UNNAMED_3_ADR45XX_I16_VIN: C1.2(N2) C2.1 R1.2(N2) U2.2
UNNAMED_3_ADR45XX_I16_VOUT: C5.1 R3.1 U2.6(VOUT)
UNNAMED_3_NC2P_I68_N1: P5.1 R3.2(N2)
UNNAMED_7_ADLT3080_I683_OUT1: C16.2(N2) R13.1 U4.1 U4.2 U4.3 U4.PAD
UNNAMED_7_ADLT3080_I683_SET: C15.2(N2) R10.2(N2) U4.4
UNNAMED_7_CAP_I577_N1: C27.1 R31.1 U5.9 U5.10
UNNAMED_7_CAP_I582_N1: C23.1 R23.1 U5.7(SET)
UNNAMED_7_CAP_I609_N1: C28.1 R33.1 U6.9 U6.10
UNNAMED_7_CAP_I616_N1: C24.1 R24.2(N2) U6.7(SET)
UNNAMED_7_CAP_I625_N1: C29.1 E2.1 E3.1 R35.1 U7.9 U7.10
UNNAMED_7_CAP_I630_N1: C25.1 R25.2(N2) U7.7(SET)
UNNAMED_7_CAP_I647_N1: C26.1 R26.2(N2) U8.8
UNNAMED_7_CAP_I648_N1: C30.1 R36.1 U8.10 U8.11 U8.12
UNNAMED_7_CAP_I701_N1: C13.1 L1.1 U3.1
UNNAMED_7_CAP_I701_N2: C13.2(N2) D1.A(P) L1.4(N4)
UNNAMED_7_CAP_I708_N1: C17.1 L1.3 R11.2(N2) R14.1
UNNAMED_7_CAP_I725_N1: C68.1 R88.1 U14.9 U14.10
UNNAMED_7_CAP_I731_N1: C67.1 R85.1 U14.7(SET)
UNNAMED_7_CAP_I738_N1: C3.1 E4.1 E5.1 P8.2(N2) UNK3.3V.1
UNNAMED_7_CNTP1P_I534_N1: EXTPWR.1(N1) JP2.3
UNNAMED_7_FERRITE_I431_N1: E1.1 JP2.2(COM)
UNNAMED_7_LINLT1931_I684_NFB: R11.1 R12.2(N2) U3.3
UNNAMED_7_LINLT3042_I575_EN: R15.1 R16.2(N2) U5.3
UNNAMED_7_LINLT3042_I575_ILIM: R27.2(N2) U5.5
UNNAMED_7_LINLT3042_I610_EN: R17.1 R18.2(N2) U6.3
UNNAMED_7_LINLT3042_I610_ILIM: R28.2(N2) U6.5
UNNAMED_7_LINLT3042_I626_EN: R19.1 R20.1 U7.3
UNNAMED_7_LINLT3042_I626_ILIM: R30.2(N2) U7.5
UNNAMED_7_LINLT3042_I726_EN: R2.1 R84.2(N2) U14.3
UNNAMED_7_LINLT3042_I726_ILIM: R86.2(N2) U14.5
UNNAMED_7_LINLT3094_I642_EN: R21.1 R22.2(N2) U8.3
UNNAMED_7_LINLT3094_I642_ILIM: R29.2(N2) U8.6
UNNAMED_8_ADLTC238718_I172_CNV: JP10.2(COM) U1.27
UNNAMED_8_ADLTC238718_I172_CNV_1: JP9.2(COM) U1.28
UNNAMED_8_ADLTC238718_I172_IN: C41.1 C42.1 R53.2(N2) TP11.1(N1) U1.2
UNNAMED_8_ADLTC238718_I172_IN_1: C41.2(N2) C43.1 R54.2(N2) TP12.1(N1) U1.3
UNNAMED_8_ADLTC238718_I172_PDN: P1.2 R32.1 U1.13
UNNAMED_8_ADLTC238718_I172_TESTPAT: P2.2 R55.1 U1.14
UNNAMED_8_ADLTC238718_I172_TWOLANES: P3.2 R34.1 U1.25
UNNAMED_8_NC3PJMPR_I256_COM: JP6.2(COM) R53.1
UNNAMED_8_NC3PJMPR_I257_COM: JP7.2(COM) R54.1
UNNAMED_10_CN160PCDGHV2_I85_TDI: P4.D30 P4.D31
UNNAMED_11_ADA49451_I55_: C58.1 R63.2(N2) R68.1 R69.1 U10.3
UNNAMED_11_ADA49451_I55__1: C60.1 R62.2(N2) R70.1 R72.1 U10.2
UNNAMED_11_ADA49451_I55__2: R71.2(N2) R74.1 U10.8
UNNAMED_11_ADA49451_I55__3: R73.2(N2) R75.1 U10.13
UNNAMED_11_ADA49451_I55_DGND: R65.2(N2) R67.2(N2) U10.16
UNNAMED_11_ADA49451_I55_DISABLEN: R76.2(N2) U10.12
UNNAMED_11_ADA49451_I55_MODE: R64.2(N2) R66.2(N2) U10.5
UNNAMED_11_CAP_I59_N1: C56.1 JP11.3 R60.2(N2) R62.1
UNNAMED_11_CAP_I59_N2: C56.2(N2) JP12.1 R61.1 R63.1
UNNAMED_11_CNBNC5P_I184_CNTR: J1.1 R59.2(N2) TP14.1(N1)
UNNAMED_11_CNBNC5P_I186_CNTR: J2.1 R58.2(N2) TP15.1(N1)
UNNAMED_11_NC3PJMPR_I180_COM: JP11.2(COM) R59.1
UNNAMED_11_NC3PJMPR_I181_COM: JP12.2(COM) R58.1
UNNAMED_12_741G04V2_I168_Y: JP14.3 U12.4(Y)
UNNAMED_12_741G74V3_I179_CLK: R80.2(N2) U13.1
UNNAMED_12_741G74V3_I179_CLRN: R82.2(N2) U13.6
UNNAMED_12_741G74V3_I179_Q: R83.1 U13.5
UNNAMED_12_ADG3241_I155_A: JP14.2(COM) TP16.1(N1) U11.3 U15.2
UNNAMED_12_ADG3241_I155_B: R80.1 U11.4
UNNAMED_12_ADG3241_I155_SELN: R37.1 U11.6
UNNAMED_12_CAP_I66_N1: C64.1 R77.2(N2)
UNNAMED_12_CAP_I66_N2: C64.2(N2) R78.1 R79.2(N2) U12.2
UNNAMED_12_CNBNC5P_I167_CNTR: J3.1 R77.1
UNNAMED_12_NC3PJMPR_I170_A: JP14.1 Y1.3
UNNAMED_12_RES_I161_N1: R45.1 R46.2(N2) Y1.1
VCM: C61.1 R7.2(N2) R9.2(N2) U10.9(VOCM)
VCM_OUT: C45.1 R4.1 R7.1 U1.32

Pads without a net: P4 C2 C3 C6 C7 C14 C15 C18 C19 C26 C27 D1 D4 D5 D11 D12 D14 D15 D17 D18 D20 D21 D23 D24 D26 D27 D29 D33 D34 G9 G12 G13 G15 G16 G19 G22 G25 G27 G28 G30 G31 G33 G34 G36 G37 G39 H1 H13 H14 H16 H17 H19 H20 H22 H23 H25 H26 H28 H29 H31 H32 H34 H35 H37 H38 H40; U2 1 3 5 7 8; U4 6; U5 4; U6 4; U7 4; U8 4 7; U10 1 4; U12 1 5; U13 3; U14 4; U15 3 5 6

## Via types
v1: diameter 0.508, hole 0.254, TOP to BOTTOM, 717 vias

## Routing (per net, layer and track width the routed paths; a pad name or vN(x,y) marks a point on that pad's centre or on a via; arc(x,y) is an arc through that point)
+2.5V: length 10.5
  TOP w0.3: U13.2 U13.7 48.89,54.3 48.67,54.09 48.67,53.61
  TOP w0.5: TP9.1 R35.2
  L3_PWR w0.5: 62.36,19.89 TP9.1 63.39,18.86
  vias: v1(47.93,52.89) v1(48.69,52.91)
+3.3V: length 11.1
  TOP w0.2: 64.92,65.53 U12.6
  TOP w0.35: P8.1 42.05,4.11
  TOP w0.5: v1(41.78,7.24) R88.2 P8.1 ; 42.05,4.11 TP18.1 ; 64.92,65.53 C65.1 v1(63.68,66.34) R78.2
  vias: v1(73.41,64.64) v1(73.79,65.28) v1(74.17,64.64) v1(74.42,65.28) v1(74.8,64.64)
+3.3V_CRYSTAL: length 19.4
  TOP w0.2: 40.56,64.51 42.26,62.81 Y1.4 C62.2 46.39,62.81 C63.1 v1(47.75,61.09)
  TOP w0.203: 40.56,64.51 R45.2
  TOP w0.5: 45.7,16.46 E4.2 46.32,17.02
  vias: v1(45.47,17.27) v1(45.47,16.51) v1(46.23,17.27)
+3.3V_TRANSLATOR: length 5.3
  TOP w0.2: v1(64.15,50.46) R37.2 C34.1 U11.5
  TOP w0.5: 49.15,17.02 E5.2 48.53,16.46
  vias: v1(48.26,17.27) v1(48.26,16.51) v1(49.15,17.27)
+6.8V: length 7.7
  TOP w0.35: P6.1 26.68,4.11
  TOP w0.5: R31.2 P6.1 ; R1.1 v1(33.15,27.05) ; 26.68,4.11 TP7.1
  vias: v1(52.7,32.59) v1(52.7,31.88)
+7.5V: length 41.2
  TOP w0.2: U14.2 39.63,14.68 39.43,14.48 38.04,14.48 37.64,14.08 37.64,12.06 38.13,11.57 U14.6
  TOP w0.3: U7.6 v1(69.09,12.78) ; U6.6 v1(58.57,12.73) ; U5.6 v1(22.15,11.1)
  TOP w0.5: TP1.1 R13.2
  L3_PWR w0.5: 70.1,18.88 TP1.1 ; TP1.1 70.1,20.94 ; TP1.1 71.13,19.91 ; TP1.1 69.08,19.91
  BOTTOM w0.3: v1(53.77,8) 57.2,8 58.57,9.38 v1(58.57,12.73) ; v1(27.1,15.88) 23.29,15.88 22.15,14.73 v1(22.15,11.1) ; v1(69.09,12.78) 69.09,9.1 67.99,8 v1(64.19,8)
  vias: v1(27.86,15.88) v1(42.47,16) v1(43.23,16) v1(53.01,8) v1(63.42,8)
+12V:
  vias: v1(71.63,41.02) v1(72.26,41.02) v1(72.9,41.02) v1(79.25,26.92) v1(79.76,26.92) v1(81.03,13.59) v1(81.03,12.83) v1(84.58,37.08) v1(84.58,36.45)
+12V_FMC: length 28.1
  TOP w0.381: JP2.1 94.03,9.5 94.41,9.88 v1(94.41,14.48)
  BOTTOM w0.305: P4.C37 93.98,14.05 v1(94.41,14.48) 94.41,16.28 94.11,16.59 P4.C35
-1V: length 6.9
  TOP w0.35: P7.1 11.48,4.11
  TOP w0.5: 11.48,4.11 TP10.1 ; P7.1 R36.2
-3V: length 9.1
  TOP w0.2: U8.5 7.21,13.34
  TOP w0.381: TP3.1 R14.2
  L3_PWR w0.5: TP3.1 71.13,29.48 ; TP3.1 70.1,28.45 ; TP3.1 70.1,30.51 ; TP3.1 69.08,29.48
  vias: v1(6.86,13.46) v1(6.86,12.45) v1(7.49,13.46) v1(7.49,12.45) v1(8.25,13.46) v1(8.25,12.45) v1(8.89,13.46) v1(8.89,12.45) v1(12.95,17.14) v1(12.95,16.38)
AGND: length 247.6
  TOP w0.2: U12.3 v1(64.11,63.68) ; C17.2 76.44,28.31 ; A1.2 55.36,25.66 ; v1(23.76,13.21) U5.8 ; U14.PAD U14.8
  TOP w0.5: JP10.3 54.99,49.23 ; JP10.3 55.91,48.26 ; JP10.3 54.99,47.29 ; R22.1 10.47,17.58 ; R22.1 9.8,18.34 ; R22.1 9.14,17.58 ; 35.81,9.02 C67.2 ; C67.2 36.73,10.08 ; C67.2 36.73,7.95 ; 46.68,65.9 C63.2 ; C63.2 47.75,66.61 ; C63.2 48.82,65.9 ; C63.2 47.75,65.19 ; R26.1 5.43,7.62 ; R26.1 4.77,6.86 ; R26.1 4.11,7.62 ; R26.1 4.77,8.38 ; C23.2 21.35,9.96 ; C23.2 21.35,7.82 ; C23.2 20.44,8.89 ; 35.43,28.8 C2.2 ; C2.2 36.96,27.35 ; C2.2 35.43,27.35 ; R27.1 21.84,13.61 ; R27.1 20.32,13.61 ; R27.1 21.08,14.28 ; R27.1 21.08,12.95 ; R84.1 41.49,18.67 ; R84.1 40.83,19.43 ; R84.1 40.17,18.67 ; 4.94,42.5 GND.1 ; GND.1 6.73,40.71 ; GND.1 8.52,42.5 ; GND.1 6.73,44.29 ; C62.1 46.42,64.61 ; C62.1 45.46,65.4 ; C62.1 44.49,64.61 ; C62.1 45.46,63.82 ; 47.51,35.69 C44.2 46.77,36.45 ; C1.1 35.43,27.35 ; C1.1 33.91,28.8 ; C1.1 35.43,28.8 ; 67.25,52.2 U11.2 66.2,52.2 ; C53.2 92.33,27.76 ; C53.2 90.8,27.76 ; C53.2 91.57,28.5 ; 69.89,13.98 C25.2 ; C25.2 69.89,16.12 ; C25.2 70.8,15.05 ; C65.2 67.26,66.34 ; C65.2 66.52,67.1 ; C65.2 66.52,65.58 ; 34.46,56.71 Y1.2 ; Y1.2 34.46,58.75 ; Y1.2 32.95,57.73 ; Y1.2 35.97,57.73 ; R30.1 69.22,5.84 ; R30.1 68.45,5.18 ; R30.1 69.22,4.52 ; R30.1 69.98,5.18 ; 20.32,46.38 R60.1 ; R60.1 20.32,47.7 ; R60.1 21.08,47.04 ; R60.1 19.56,47.04 ; R25.1 69.68,17.75 ; R25.1 69.02,16.99 ; R25.1 70.35,16.99 ; R25.1 69.68,16.23 ; 60.96,52.2 C34.2 ; C34.2 61.7,52.96 ; C34.2 61.7,51.43 ; C45.2 46.83,46.64 ; C45.2 46.09,45.87 ; C45.2 46.83,45.11 ; R23.2 21.56,7.62 ; R23.2 21.56,6.1 ; R23.2 22.22,6.86 ; R23.2 20.9,6.86 ; R24.1 59.17,17.76 ; R24.1 59.83,16.99 ; R24.1 59.17,16.23 ; R24.1 58.51,16.99 ; 20.32,37.52 R61.2 ; R61.2 21.08,38.18 ; R61.2 19.56,38.18 ; R61.2 20.32,38.84 ; C24.2 59.37,16.12 ; C24.2 60.29,15.05 ; C24.2 59.37,13.98 ; 39.56,46.93 C42.2 38.8,47.67 ; 4.39,16.07 R29.1 ; R29.1 5.72,16.07 ; R29.1 5.06,16.83 ; R29.1 5.06,15.31 ; 57.91,22.53 R6.2 ; R6.2 58.67,23.19 ; R6.2 57.91,23.85 ; 37.11,27.14 U2.4 ; U2.4 38.46,26.56 ; U2.4 39.82,27.14 ; 36.93,6.32 R85.2 ; R85.2 36.93,7.85 ; R85.2 37.59,7.09 ; R85.2 36.27,7.09 ; U11.1 67.25,51.55 ; U11.1 66.2,51.55 ; U11.1 66.73,51.08 ; R28.1 58.42,5.84 ; R28.1 59.18,5.18 ; R28.1 58.42,4.52 ; R46.1 32.77,59.09 ; R46.1 32,59.75 ; R46.1 31.24,59.09 ; R46.1 32,58.43 ; 24.8,18.54 R16.1 ; R16.1 25.46,19.3 ; R16.1 26.12,18.54 ; 55.17,23.24 C8.2 54.41,22.51 ; U13.4 55.11,55.6 ; U13.4 53.26,55.6 ; U13.4 54.18,56.02 ; 61.09,65.68 R79.1 61.09,67 ; C26.2 4.57,10.68 ; C26.2 3.65,9.61 ; C26.2 4.57,8.54 ; 46.23,25.59 C5.2 ; C5.2 45.16,26.5 ; C5.2 47.29,26.5 ; R86.1 36.45,14.32 ; R86.1 36.45,13 ; R86.1 35.69,13.66 ; 39.56,38.28 C43.2 38.8,37.55
  L2_GND w0.5: 4.94,42.5 GND.1 ; GND.1 8.52,42.5 ; GND.1 6.73,40.71 ; GND.1 6.73,44.29
  L3_PWR w0.5: 6.73,40.71 GND.1 ; GND.1 8.52,42.5 ; GND.1 6.73,44.29 ; GND.1 4.94,42.5
  BOTTOM w0.5: v1(87.46,14.68) P4.H36 v1(87.46,15.95) P4.G35 ; GND.1 6.73,44.29 ; GND.1 4.94,42.5 ; GND.1 8.52,42.5 ; GND.1 6.73,40.71 ; v1(92.54,37.54) P4.D19 v1(92.54,36.27) P4.C20 v1(92.54,35) P4.C21 v1(92.54,33.73) 91.91,33.09 v1(92.54,32.46) ; C61.2 37.27,42.16 ; C61.2 38,41.4 ; C61.2 37.27,40.64 ; 88.09,12.77 v1(87.46,12.14) P4.H39 v1(87.46,10.87) 88.09,10.23 ; v1(92.54,56.59) P4.C4 v1(92.54,55.32) P4.C5 v1(92.54,54.05) 91.91,53.41 v1(92.54,52.78) P4.D7 v1(92.54,51.51) P4.C8 v1(92.54,50.24) P4.C9 v1(92.54,48.97) P4.D10 v1(92.54,47.7) ; R65.1 30.01,49.64 ; R65.1 30.01,48.32 ; R65.1 29.25,48.98 ; R65.1 30.77,48.98 ; v1(88.87,50.88) P4.G8 v1(87.46,51.51) ; v1(87.46,22.3) 86.83,22.94 v1(87.46,23.57) P4.G29 ; R75.2 35.52,48.98 ; R75.2 34,48.98 ; R75.2 34.76,49.64 ; R75.2 34.76,48.32 ; 29.25,36.11 R64.1 ; R64.1 30.77,36.11 ; R64.1 30.01,35.45 ; R64.1 30.01,36.77 ; P4.D3 v1(92.54,57.86) P4.D2 ; v1(92.54,45.16) P4.D13 v1(92.54,43.89) P4.C13 v1(92.54,45.16) ; v1(92.54,45.16) P4.C12 v1(92.54,46.43) ; v1(87.46,29.92) P4.H24 v1(87.46,31.19) P4.G23 v1(87.46,32.46) ; v1(92.54,31.19) P4.C24 v1(92.54,29.92) ; v1(92.54,38.81) P4.C17 ; v1(92.54,29.92) P4.D25 v1(92.54,28.65) P4.C25 v1(92.54,29.92) ; v1(87.46,37.54) P4.H18 v1(87.46,38.81) P4.G17 ; v1(92.54,59.13) P4.C1 v1(92.54,60.4) ; 86.83,53.41 v1(87.46,54.05) P4.G5 v1(87.46,55.32) P4.G4 v1(87.46,56.59) P4.H3 ; v1(87.46,28.65) P4.G26 v1(87.46,27.38) P4.H27 v1(87.46,26.11) ; v1(92.54,23.57) P4.C29 93.17,24.22 v1(92.55,24.85) ; v1(92.55,24.85) 91.92,25.48 91.91,25.48 v1(91.27,24.84) ; v1(92.55,24.85) 93.17,25.48 ; v1(92.54,18.49) P4.C33 v1(92.54,19.76) P4.C32 v1(92.54,21.03) ; v1(87.46,18.49) P4.H33 v1(87.46,19.76) P4.G32 v1(87.46,21.03) ; P4.H9 v1(86.05,49.6) ; v1(87.46,36.27) P4.G20 v1(87.46,35) P4.H21 v1(87.46,33.73) ; v1(87.46,47.7) P4.G11 ; 93.17,10.23 v1(93.81,10.87) ; v1(87.37,45.25) P4.H12 ; P4.H2 v1(87.46,59.13) P4.G1 v1(87.46,60.4) ; v1(91.27,12.14) P4.D39 v1(91.27,10.87) ; v1(92.54,15.95) P4.C36 v1(92.54,14.68) P4.D37 v1(92.54,13.41) v1(93.81,12.14) ; P4.G14 v1(88.64,43.8) ; v1(87.37,42.53) P4.H15 ; v1(92.54,40.08) P4.D16 v1(92.54,41.35) P4.C16 v1(92.54,40.08)
  vias: v1(3.82,59.08) v1(3.82,54) v1(3.82,48.92) v1(3.82,43.84) v1(3.82,38.76) v1(3.82,33.68) v1(3.82,28.6) v1(3.82,23.52) v1(3.82,18.44) v1(3.82,13.36) v1(3.82,8.28) v1(6.36,66.7) v1(6.36,56.54) v1(6.36,51.46) v1(6.36,46.38) v1(6.36,36.22) v1(6.36,31.14) v1(6.36,26.06) v1(6.36,20.98) v1(6.36,5.74) v1(7.8,9.78) v1(7.92,10.41) v1(8.56,10.03) v1(8.9,64.16) v1(8.9,59.08) v1(8.9,54) v1(8.9,48.92) v1(8.9,43.84) v1(8.9,38.76) v1(8.9,33.68) v1(8.9,28.6) v1(8.9,23.52) v1(9.95,7.85) v1(9.95,6.96) v1(10.29,8.7) v1(10.69,8.11) v1(10.97,14.99) v1(11.18,19.69) v1(11.44,66.7) v1(11.44,61.62) v1(11.44,56.54) v1(11.44,51.46) v1(11.44,46.38) v1(11.44,41.3) v1(11.44,36.22) v1(11.44,31.14) v1(11.44,26.06) v1(11.44,20.98) v1(11.44,5.74) v1(11.73,14.99) v1(11.81,19.69) v1(12.45,19.69) v1(12.5,14.99) v1(13.26,14.99) v1(13.72,54) v1(13.72,48.92) v1(13.72,43.84) v1(13.72,38.76) v1(13.72,33.68) v1(13.77,28.7) v1(13.72,23.52) v1(13.72,18.44) v1(13.98,64.16) v1(13.98,59.08) v1(13.98,13.36) v1(13.98,8.28) v1(16.52,66.7) v1(16.52,61.62) v1(16.52,56.54) v1(16.52,51.46) v1(16.52,41.3) v1(16.52,31.14) v1(16.52,26.06) v1(16.52,20.98) v1(16.52,10.82) v1(16.52,5.74) v1(17.53,8.51) v1(18.03,8) v1(18.54,8.51) v1(19.06,64.16) v1(19.06,59.08) v1(19.06,54) v1(19.06,23.52) v1(19.06,13.36) v1(19.06,3.2) v1(19.23,48.89) v1(19.23,43.81) v1(19.35,38.73) v1(19.31,28.47) v1(19.44,33.55) v1(20.19,8.64) v1(20.19,8) v1(20.19,7.37) v1(20.19,6.73) v1(20.19,6.1) v1(21.6,66.7) v1(21.6,61.62) v1(21.6,56.54) v1(21.6,46.38) v1(21.6,31.14) v1(21.6,26.06) v1(21.6,20.98) v1(22.02,51.43) v1(23.11,13.72) v1(23.11,13.21) v1(23.11,12.7) v1(23.75,13.72) v1(23.75,12.7) v1(24.14,64.16) v1(24.14,59.08) v1(24.14,54) v1(24.14,48.92) v1(24.14,38.76) v1(24.14,33.68) v1(24.14,28.6) v1(24.38,13.72) v1(24.38,13.21) v1(24.38,12.7) v1(26.68,66.7) v1(26.68,61.62) v1(26.68,56.54) v1(26.68,51.46) v1(26.68,46.38) v1(26.63,31.46) v1(26.68,26.06) v1(26.68,20.98) v1(28.57,32.13) v1(28.57,31.37) v1(28.57,18.54) v1(28.62,43.58) v1(28.62,41.66) v1(28.96,19.05) v1(29.22,64.16) v1(29.22,59.08) v1(29.21,58.04) v1(29.21,57.4) v1(29.21,56.77) v1(29.22,54) v1(29.22,28.6) v1(29.22,23.52) v1(29.34,50.55) v1(29.34,18.54) v1(29.97,50.55) v1(30.48,35.18) v1(30.48,34.54) v1(30.48,33.91) v1(30.61,50.55) v1(31.76,66.7) v1(31.76,56.54) v1(31.76,51.46) v1(31.75,50.55) v1(31.76,31.14) v1(31.76,26.06) v1(31.76,20.98) v1(32,34.8) v1(32.26,34.29) v1(32.38,50.55) v1(32.64,34.8) v1(32.77,8.38) v1(33.02,50.55) v1(33.4,13.08) v1(33.66,8.38) v1(33.91,50.55) v1(34.09,27.05) v1(34.15,35.05) v1(34.3,59.08) v1(34.3,54) v1(34.3,23.52) v1(34.3,18.44) v1(34.3,3.2) v1(34.54,50.55) v1(34.86,35.06) v1(35.18,50.55) v1(35.36,27.05) v1(35.43,35.05) v1(36.07,12.83) v1(36.07,11.05) v1(36.07,10.29) v1(36.12,26.67) v1(36.32,5.21) v1(36.7,4.7) v1(36.84,66.7) v1(36.84,61.62) v1(36.84,56.54) v1(36.84,51.46) v1(36.88,27.05) v1(36.84,20.98) v1(36.83,12.83) v1(36.83,10.29) v1(37.08,5.21) v1(37.22,26.22) v1(37.64,25.65) v1(38.07,26.22) v1(38.23,41.66) v1(38.4,37.21) v1(38.48,13.84) v1(38.48,13.34) v1(38.48,12.83) v1(38.86,41.66) v1(39.14,47.88) v1(39.12,37.21) v1(39.12,13.84) v1(39.13,13.34) v1(39.12,12.83) v1(39.38,59.08) v1(39.38,54) v1(39.38,43.84) v1(39.38,23.52) v1(39.54,48.52) v1(39.75,13.84) v1(39.75,13.34) v1(39.75,12.83) v1(39.85,47.88) v1(41.15,38.61) v1(41.92,61.62) v1(41.92,56.54) v1(41.92,51.46) v1(41.92,46.38) v1(41.92,20.98) v1(43.81,18.8) v1(44.2,19.18) v1(44.46,59.08) v1(44.46,54) v1(44.46,48.92) v1(44.46,38.76) v1(44.46,33.68) v1(44.46,13.36) v1(44.46,8.28) v1(44.58,18.8) v1(44.7,65.79) v1(45.47,65.79) v1(45.59,46.48) v1(45.59,45.85) v1(45.59,45.21) v1(45.64,25.4) v1(46.02,24.77) v1(46.23,65.79) v1(46.4,36.83) v1(46.4,25.4) v1(46.99,66.93) v1(47,56.54) v1(47,20.98) v1(47.75,66.93) v1(47.88,8.25) v1(48.39,66.93) v1(48.64,8.25) v1(49.54,64.16) v1(49.54,59.08) v1(49.52,50.8) v1(49.52,50.04) v1(49.54,18.44) v1(49.54,13.36) v1(49.54,8.28) v1(49.54,3.2) v1(49.71,28.7) v1(50.04,42.93) v1(50.04,42.29) v1(50.04,41.66) v1(50.04,41.02) v1(50.04,40.39) v1(50.67,42.93) v1(50.67,42.29) v1(50.67,41.66) v1(50.67,41.02) v1(50.67,40.39) v1(51.23,31.12) v1(51.23,26.29) v1(51.31,42.93) v1(51.31,42.29) v1(51.31,41.66) v1(51.31,41.02) v1(51.31,40.39) v1(51.94,50.04) v1(51.94,42.93) v1(51.94,42.29) v1(51.94,41.66) v1(51.94,41.02) v1(51.94,40.39) v1(52.08,56.54) v1(52.08,20.98) v1(52.08,15.9) v1(52.58,42.93) v1(52.58,42.29) v1(52.58,41.66) v1(52.58,41.02) v1(52.58,40.39) v1(52.7,3.81) v1(52.75,55.63) v1(53.34,3.81) v1(53.97,3.81) v1(54.08,44.07) v1(54.53,49.78) v1(54.62,59.08) v1(54.62,18.44) v1(54.79,44.07) v1(54.86,4.19) v1(55,50.35) v1(55.04,33.78) v1(55.17,38.99) v1(55.17,38.1) v1(55.24,22.23) v1(55.24,3.68) v1(55.37,24.13) v1(55.42,49.78) v1(55.63,4.19) v1(56.18,33.78) v1(56.39,11.18) v1(56.39,10.67) v1(56.39,10.16) v1(56.44,38.99) v1(56.77,32.64) v1(56.77,31.88) v1(56.95,44.6) v1(57.02,11.18) v1(57.03,10.67) v1(57.02,10.16) v1(57.16,31.14) v1(57.16,26.06) v1(57.16,20.98) v1(57.4,32.26) v1(57.66,11.18) v1(57.66,10.67) v1(57.66,10.16) v1(58.04,4.06) v1(58.42,3.56) v1(58.8,13.59) v1(58.8,4.06) v1(59.05,18.41) v1(59.18,44.12) v1(59.44,13.59) v1(59.7,59.08) v1(59.7,48.92) v1(59.7,28.6) v1(59.7,23.52) v1(59.7,18.44) v1(59.7,8.28) v1(59.82,44.12) v1(60.07,13.59) v1(60.45,44.12) v1(60.5,38.99) v1(60.63,51.82) v1(60.63,51.1) v1(62.24,61.62) v1(62.24,26.06) v1(62.24,20.98) v1(63.12,3.81) v1(63.75,3.81) v1(64.39,3.81) v1(64.78,59.08) v1(64.78,3.2) v1(64.82,54.23) v1(65.28,4.32) v1(65.79,67.44) v1(65.79,3.81) v1(66.29,4.32) v1(66.55,67.44) v1(66.8,11.18) v1(66.8,10.67) v1(66.8,10.16) v1(67.31,67.44) v1(67.32,36.22) v1(67.32,31.14) v1(67.32,26.06) v1(67.32,20.98) v1(67.44,11.18) v1(67.45,10.67) v1(67.44,10.16) v1(67.61,52.2) v1(67.61,51.49) v1(67.74,59.56) v1(67.74,58.8) v1(67.74,58.04) v1(68.07,11.18) v1(68.07,10.67) v1(68.07,10.16) v1(68.83,4.19) v1(69.22,3.68) v1(69.6,4.19) v1(69.86,64.16) v1(69.86,38.76) v1(69.86,33.68) v1(69.86,23.52) v1(69.86,8.28) v1(69.86,3.2) v1(71.43,16.46) v1(71.42,15.75) v1(71.42,15.03) v1(71.42,14.32) v1(72.4,66.7) v1(72.4,31.14) v1(72.52,20.96) v1(72.52,10.82) v1(72.52,5.74) v1(72.69,15.88) v1(72.9,24.51) v1(72.9,23.88) v1(72.9,23.24) v1(74.94,54) v1(74.94,38.76) v1(74.94,18.44) v1(75.44,14.86) v1(75.56,27.18) v1(75.82,34.54) v1(75.82,33.78) v1(75.82,33.02) v1(76.33,27.18) v1(76.33,14.86) v1(76.83,60.07) v1(76.83,59.31) v1(77.09,27.18) v1(77.22,14.86) v1(77.47,60.07) v1(77.48,10.82) v1(77.48,5.74) v1(77.98,14.86) v1(78.49,63.63) v1(78.49,62.86) v1(78.49,62.1) v1(78.49,61.34) v1(78.54,28.07) v1(79.04,49.63) v1(79.42,32.89) v1(80.02,64.16) v1(80.02,59.08) v1(80.02,38.76) v1(80.02,23.52) v1(82.05,34.04) v1(82.3,26.67) v1(82.3,25.91) v1(82.3,25.15) v1(82.3,21.21) v1(82.3,20.45) v1(82.3,19.69) v1(82.3,18.92) v1(82.3,18.16) v1(82.3,17.4) v1(82.42,39.37) v1(82.56,66.7) v1(82.56,61.62) v1(82.56,31.14) v1(82.56,15.9) v1(82.56,10.82) v1(83.19,39.37) v1(83.95,39.37) v1(85.1,64.16) v1(85.1,33.68) v1(85.1,28.6) v1(85.1,23.52) v1(85.1,18.44) v1(85.01,12.45) v1(85.01,7.62) v1(85.1,3.2) v1(89.08,7.62) v1(89.41,21.1) v1(89.44,16.01) v1(90.18,64.16) v1(90.3,28.07) v1(90.3,27.43) v1(90.35,26.67) v1(90.93,28.96) v1(92.72,66.7) v1(92.72,61.62) v1(92.72,5.74) v1(94.23,28.07) v1(94.23,24.38) v1(95.26,64.16) v1(95.26,59.08) v1(95.26,54) v1(95.26,48.92) v1(95.26,43.84) v1(95.26,38.76) v1(95.26,33.68) v1(95.26,28.6) v1(95.26,23.52) v1(95.26,18.44) v1(95.26,13.36) v1(95.26,8.28) v1(95.26,3.2) v1(95.76,19.3) v1(96.52,19.3) v1(97.28,19.3) v1(97.8,66.7) v1(97.8,61.62) v1(97.8,56.54) v1(97.8,51.46) v1(97.8,46.38) v1(97.8,41.3) v1(97.8,36.22) v1(97.8,31.14) v1(97.8,15.9) v1(97.8,10.82) v1(97.8,5.74) v1(97.97,26.04) v1(97.92,21.08)
VDD: length 6
  TOP w0.2: U1.11 U1.12 v1(51.13,38.27)
  TOP w0.5: R33.2 TP8.1
  L3_PWR w0.5: 53.21,17.83 TP8.1 53.21,19.89
  vias: v1(51.79,33.91) v1(52.5,33.91) v1(53.26,33.91)
VDDL:
  vias: v1(50.21,45.54) v1(50.21,44.97) v1(64.9,17.65) v1(64.9,17.02) v1(64.9,16.38)
3P3VAUX: length 34.8
  TOP w0.5: U9.8 C53.1 91.54,26.16 90.22,24.84 v1(90.22,20.39)
  BOTTOM w0.5: TP13.1 81.49,5.97 88.95,5.97 90.22,7.24 v1(90.22,20.39) P4.D32
+3P3V_FMC: length 6.8
  BOTTOM w0.305: P4.C39 91.11,13.57 91.11,14.52 P4.D36
  BOTTOM w0.381: 91.91,10.23 P4.C39
AMP_PWR+: length 19.3
  TOP w0.2: U10.6 32.09,40.47 v1(32,40.39) ; U10.7 32.59,40.44 v1(32.64,40.39)
  TOP w0.381: 28.18,3.3 P6.2
  TOP w0.5: 30.57,16.93 C18.1 UNK+6.8V.1 28.18,3.3
  BOTTOM w0.2: R76.1 v1(37.32,42.89)
  vias: v1(31.5,37.46) v1(31.5,36.7) v1(33.27,37.46) v1(33.27,36.7) v1(33.4,17.27) v1(33.66,17.78) v1(34.04,17.27)
